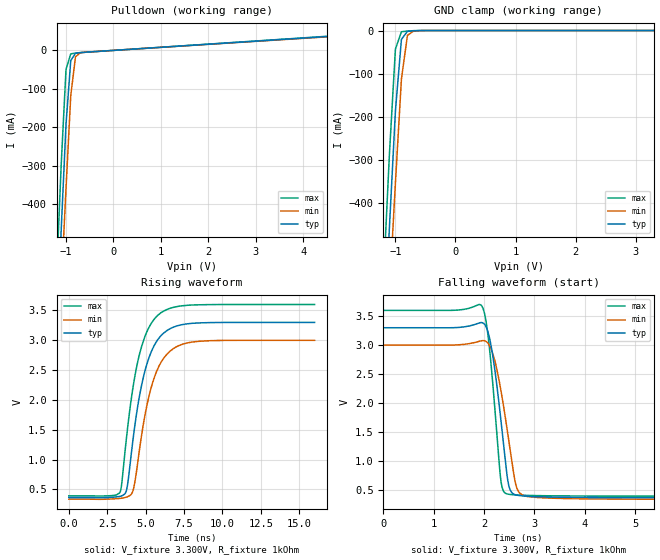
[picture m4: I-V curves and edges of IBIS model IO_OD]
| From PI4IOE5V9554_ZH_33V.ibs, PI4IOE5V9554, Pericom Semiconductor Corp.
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|   Model IO_OD
[Model]   IO_OD
Model_type  I/O_open_drain
Vref =  3.300V
Vinl = 800mV
Vinh = 2.00V
Rref = 1k
Cref = 0
Vmeas = 1.650V
| Variable   typ   min   max
C_comp   4.000p   3.950p   4.050p
[Voltage Range]   3.300V   3.000V   3.600V
[Temperature Range]   25   85   -40
[Pullup Reference]   3.300V   3.000V   3.600V
[Pulldown Reference]   0.000V   0.000V   0.000V
[POWER Clamp Reference]   3.300V   3.000V   3.600V
[GND Clamp Reference]   0.000V   0.000V   0.000V
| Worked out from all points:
|   slope of the pulldown table from 0 to 0.495 V, typ, clamps not added: 125 ohm
|   GND clamp passes 1 mA (typ) near -0.72 V on its own axis
|   falling waveform, V_fixture 3.300V, R_fixture 1kOhm: 20-80 % time 239ps typ, 293ps min, 189ps max; typ from 3.3 V to 0.365 V
|   rising waveform, V_fixture 3.300V, R_fixture 1kOhm: 20-80 % time 1.22ns typ, 1.26ns min, 1.2ns max; typ from 0.365 V to 3.3 V
[GND Clamp]
| Voltage   I(typ)   I(min)   I(max)
-3.3V     -6.408A    -6.171A    -6.722A
-1.2V     -726.7mA   -858.9mA   -579mA
-1.1V     -456.3mA   -606.1mA   -286.6mA
-1V       -186.2mA   -353.2mA   -42.87mA
-900mV    -20.42mA   -112.2mA   -2.874mA
-800mV    -1.989mA   -11.38mA   -1.219mA
-700mV    -675.6uA   -1.389mA   -381.3uA
3.3V      81.11pA    220.5pA    79.2pA
[POWER Clamp]
| Voltage   I(typ)   I(min)   I(max)
-3.3V     0A         0A         0A
3.3V      0A         0A         0A
[Pulldown]
| Voltage   I(typ)   I(min)   I(max)
-3.3V     -6.413A    -6.175A    -6.729A
-1.2V     -732.7mA   -864.2mA   -585.6mA
-1.1V     -462.3mA   -611.3mA   -293.1mA
-1V       -192.1mA   -358.5mA   -49.15mA
-900mV    -26.14mA   -117.4mA   -8.938mA
-800mV    -7.48mA    -16.44mA   -7.023mA
-700mV    -5.845mA   -6.231mA   -5.821mA
6.6V      52.6mA     51.27mA    53.64mA
[Falling Waveform]
V_fixture = 3.300V
V_fixture_min = 3.000V
V_fixture_max = 3.600V
R_fixture = 1kOhm
C_fixture = 0F
|   Time   V(typ)   V(min)   V(max)
0s        3.3V       3V         3.6V
1.95ns    3.389V     3.075V     3.681V
2.055ns   3.284V     3.053V     3.315V
2.175ns   2.805V     2.846V     2.308V
2.325ns   1.775V     2.261V     724.5mV
2.445ns   830.7mV    1.618V     434.3mV
2.52ns    497.7mV    1.18V      421.7mV
2.64ns    411.4mV    561mV      413.3mV
2.85ns    391.9mV    387.7mV    405.7mV
11ns      365.4mV    337.5mV    393.1mV
[Rising Waveform]
V_fixture = 3.300V
V_fixture_min = 3.000V
V_fixture_max = 3.600V
R_fixture = 1kOhm
C_fixture = 0F
|   Time   V(typ)   V(min)   V(max)
0s        365.4mV    337.5mV    393.1mV
3.34ns    385.1mV    350.8mV    456.5mV
3.78ns    514.6mV    374.3mV    1.426V
4.18ns    1.339V     480.3mV    2.214V
4.5ns     1.919V     977mV      2.658V
5.1ns     2.615V     1.932V     3.154V
5.94ns    3.06V      2.601V     3.451V
6.8ns     3.219V     2.859V     3.552V
8ns       3.284V     2.97V      3.591V
16ns      3.3V       3V         3.6V
[Ramp]
| Variable   typ   min   max
dV/dt_r   1.76076V/1.2225n   1.59750V/1.2573n   1.92414V/1.1936n
dV/dt_f   1.76076V/238.08p   1.59750V/291.87p   1.92414V/188.48p
R_load = 1000
